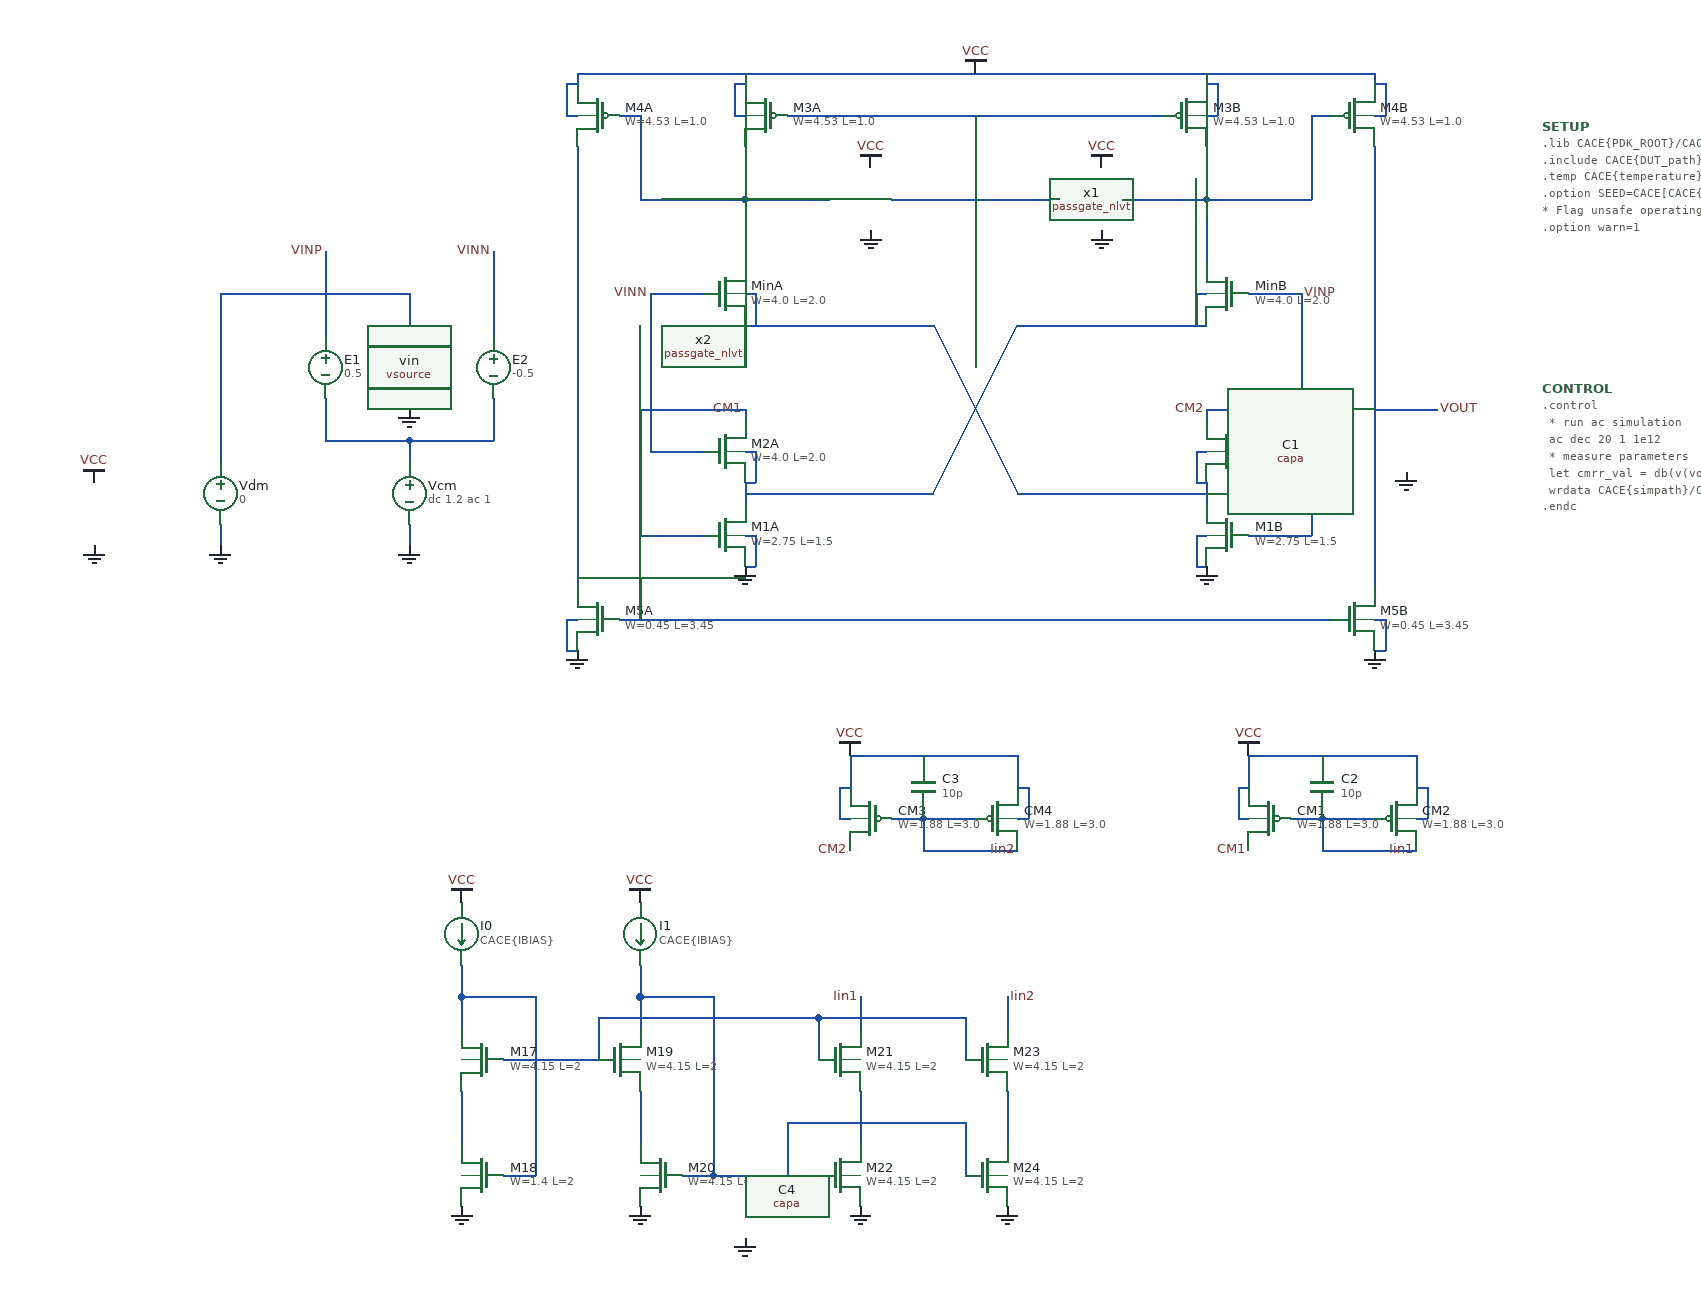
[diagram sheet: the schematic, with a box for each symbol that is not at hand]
v {xschem version=3.4.5 file_version=1.2
}
G {}
K {}
V {}
S {}
E {}
N 220 0 220 10 {
lab=CM2}
N -220 70 -220 90 {
lab=#net1}
N -320 0 -220 0 {
lab=CM1}
N -320 0 -320 120 {
lab=CM1}
N -320 120 -260 120 {
lab=CM1}
N 220 70 220 90 {
lab=#net2}
N -310 40 -260 40 {
lab=VINN}
N -310 -110 -260 -110 {
lab=VINN}
N 260 120 320 120 {
lab=CM2}
N 220 0 320 0 {
lab=CM2}
N 320 0 320 120 {
lab=CM2}
N 260 40 310 40 {
lab=VINP}
N 260 -110 310 -110 {
lab=VINP}
N -220 80 -40 80 {
lab=#net1}
N 40 -80 220 -80 {
lab=#net1}
N -220 -80 -40 -80 {
lab=#net2}
N 40 80 220 80 {
lab=#net2}
N 140 -200 220 -200 {
lab=#net3}
N -220 -200 -140 -200 {
lab=#net4}
N -80 -200 80 -200 {
lab=#net5}
N -180 -280 180 -280 {
lab=#net5}
N -380 -320 380 -320 {
lab=VCC}
N 320 -280 340 -280 {
lab=#net3}
N -340 -280 -320 -280 {
lab=#net4}
N -340 200 340 200 {
lab=#net6}
N -380 -250 -380 170 {
lab=#net6}
N -380 160 -320 160 {
lab=#net6}
N -320 160 -320 200 {
lab=#net6}
N 380 -250 380 170 {
lab=VOUT}
N -380 -320 -380 -310 {
lab=VCC}
N -220 -320 -220 -310 {
lab=VCC}
N 220 -320 220 -310 {
lab=VCC}
N 380 -320 380 -310 {
lab=VCC}
N 380 -0 440 0 {
lab=VOUT}
N -220 -110 -210 -110 {
lab=#net2}
N -210 -110 -210 -80 {
lab=#net2}
N 210 -110 220 -110 {
lab=#net1}
N 210 -110 210 -80 {
lab=#net1}
N -390 200 -380 200 {
lab=GND}
N -390 200 -390 230 {
lab=GND}
N -390 230 -380 230 {
lab=GND}
N -220 120 -210 120 {
lab=GND}
N -210 120 -210 150 {
lab=GND}
N -220 150 -210 150 {
lab=GND}
N -220 40 -210 40 {
lab=#net1}
N -210 40 -210 70 {
lab=#net1}
N -220 70 -210 70 {
lab=#net1}
N 210 120 220 120 {
lab=GND}
N 210 120 210 150 {
lab=GND}
N 210 150 220 150 {
lab=GND}
N 210 40 220 40 {
lab=#net2}
N 210 40 210 70 {
lab=#net2}
N 210 70 220 70 {
lab=#net2}
N 380 200 390 200 {
lab=GND}
N 390 200 390 230 {
lab=GND}
N 380 230 390 230 {
lab=GND}
N 220 -280 230 -280 {
lab=VCC}
N 230 -310 230 -280 {
lab=VCC}
N 220 -310 230 -310 {
lab=VCC}
N 380 -280 390 -280 {
lab=VCC}
N 390 -310 390 -280 {
lab=VCC}
N 380 -310 390 -310 {
lab=VCC}
N -230 -280 -220 -280 {
lab=VCC}
N -230 -310 -230 -280 {
lab=VCC}
N -230 -310 -220 -310 {
lab=VCC}
N -390 -280 -380 -280 {
lab=VCC}
N -390 -310 -390 -280 {
lab=VCC}
N -390 -310 -380 -310 {
lab=VCC}
N -220 0 -220 10 {
lab=CM1}
N -320 -280 -320 -200 {
lab=#net4}
N -320 -200 -220 -200 {
lab=#net4}
N 320 -280 320 -200 {
lab=#net3}
N 220 -200 320 -200 {
lab=#net3}
N -40 80 40 -80 {
lab=#net1}
N 220 -250 220 -200 {
lab=#net3}
N 220 -200 220 -140 {
lab=#net3}
N 310 -110 310 40 {
lab=VINP}
N -40 -80 40 80 {
lab=#net2}
N -310 -110 -310 40 {
lab=VINN}
N -220 -250 -220 -200 {
lab=#net4}
N -220 -200 -220 -140 {
lab=#net4}
N -0 -280 -0 -200 {
lab=#net5}
N -540 -60 -500 -60 {
lab=#net7}
N -720 -110 -720 50 {
lab=#net7}
N -720 -110 -540 -110 {
lab=#net7}
N -720 110 -720 130 {
lab=GND}
N -540 110 -540 130 {
lab=GND}
N -540 30 -460 30 {
lab=#net8}
N -540 30 -540 50 {
lab=#net8}
N -540 -20 -500 -20 {
lab=GND}
N -540 -20 -540 0 {
lab=GND}
N -620 -10 -620 30 {
lab=#net8}
N -460 -10 -460 30 {
lab=#net8}
N -540 -110 -540 -60 {
lab=#net7}
N -460 -150 -460 -70 {
lab=VINN}
N -620 -150 -620 -70 {
lab=VINP}
N -620 30 -540 30 {
lab=#net8}
N -580 -20 -540 -20 {
lab=GND}
N -580 -60 -540 -60 {
lab=#net7}
N 420 390 430 390 {
lab=VCC}
N 430 360 430 390 {
lab=VCC}
N 420 360 430 360 {
lab=VCC}
N 300 390 330 390 {
lab=Iin1}
N 330 390 380 390 {
lab=Iin1}
N 330 390 330 420 {
lab=Iin1}
N 330 420 420 420 {
lab=Iin1}
N 260 330 330 330 {
lab=VCC}
N 330 330 420 330 {
lab=VCC}
N 420 330 420 360 {
lab=VCC}
N 260 330 260 360 {
lab=VCC}
N 250 390 260 390 {
lab=VCC}
N 250 360 260 360 {
lab=VCC}
N 250 360 250 390 {
lab=VCC}
N 40 390 50 390 {
lab=VCC}
N 50 360 50 390 {
lab=VCC}
N 40 360 50 360 {
lab=VCC}
N -80 390 -50 390 {
lab=Iin2}
N -50 390 0 390 {
lab=Iin2}
N -50 390 -50 420 {
lab=Iin2}
N -50 420 40 420 {
lab=Iin2}
N -120 330 -50 330 {
lab=VCC}
N -50 330 40 330 {
lab=VCC}
N 40 330 40 360 {
lab=VCC}
N -120 330 -120 360 {
lab=VCC}
N -130 390 -120 390 {
lab=VCC}
N -130 360 -120 360 {
lab=VCC}
N -130 360 -130 390 {
lab=VCC}
N -490 560 -490 590 {
lab=#net7}
N -490 650 -490 700 {
lab=#net8}
N -450 730 -420 730 {
lab=#net7}
N -420 560 -420 730 {
lab=#net7}
N -490 560 -420 560 {
lab=#net7}
N -320 560 -320 590 {
lab=#net9}
N -320 650 -320 700 {
lab=#net10}
N -280 730 -250 730 {
lab=#net9}
N -250 560 -250 730 {
lab=#net9}
N -320 560 -250 560 {
lab=#net9}
N -110 560 -110 590 {
lab=Iin1}
N -110 650 -110 700 {
lab=#net11}
N -450 620 -420 620 {
lab=#net7}
N -250 730 -150 730 {
lab=#net9}
N -490 530 -490 560 {
lab=#net7}
N -320 530 -320 560 {
lab=#net9}
N -420 620 -360 620 {
lab=#net7}
N -360 580 -360 620 {
lab=#net7}
N -360 580 -150 580 {
lab=#net7}
N -150 580 -150 620 {
lab=#net7}
N 30 560 30 590 {
lab=Iin2}
N 30 650 30 700 {
lab=#net12}
N -10 580 -10 620 {
lab=#net7}
N -180 680 -180 730 {
lab=#net9}
N -180 680 -10 680 {
lab=#net9}
N -10 680 -10 730 {
lab=#net9}
N -150 580 -10 580 {
lab=#net7}
C {sky130_fd_pr/nfet_01v8.sym} 240 120 0 1 {name=M1B
W=2.75
L=1.5
nf=1
mult=1
ad="'int((nf+1)/2) * W/nf * 0.29'" 
pd="'2*int((nf+1)/2) * (W/nf + 0.29)'"
as="'int((nf+2)/2) * W/nf * 0.29'" 
ps="'2*int((nf+2)/2) * (W/nf + 0.29)'"
nrd="'0.29 / W'" nrs="'0.29 / W'"
sa=0 sb=0 sd=0
model=nfet_01v8
spiceprefix=X
}
C {sky130_fd_pr/nfet_01v8.sym} 240 40 0 1 {name=M2B
W=4.0
L=2.0
nf=1
mult=1
ad="'int((nf+1)/2) * W/nf * 0.29'" 
pd="'2*int((nf+1)/2) * (W/nf + 0.29)'"
as="'int((nf+2)/2) * W/nf * 0.29'" 
ps="'2*int((nf+2)/2) * (W/nf + 0.29)'"
nrd="'0.29 / W'" nrs="'0.29 / W'"
sa=0 sb=0 sd=0
model=nfet_01v8
spiceprefix=X
}
C {devices/gnd.sym} 220 150 0 0 {name=l1 lab=GND}
C {devices/lab_pin.sym} -310 -110 0 0 {name=p1 sig_type=std_logic lab=VINN}
C {sky130_fd_pr/nfet_01v8.sym} -240 120 0 0 {name=M1A
W=2.75
L=1.5
nf=1
mult=1
ad="'int((nf+1)/2) * W/nf * 0.29'" 
pd="'2*int((nf+1)/2) * (W/nf + 0.29)'"
as="'int((nf+2)/2) * W/nf * 0.29'" 
ps="'2*int((nf+2)/2) * (W/nf + 0.29)'"
nrd="'0.29 / W'" nrs="'0.29 / W'"
sa=0 sb=0 sd=0
model=nfet_01v8
spiceprefix=X
}
C {sky130_fd_pr/nfet_01v8.sym} -240 40 0 0 {name=M2A
W=4.0
L=2.0
nf=1
mult=1
ad="'int((nf+1)/2) * W/nf * 0.29'" 
pd="'2*int((nf+1)/2) * (W/nf + 0.29)'"
as="'int((nf+2)/2) * W/nf * 0.29'" 
ps="'2*int((nf+2)/2) * (W/nf + 0.29)'"
nrd="'0.29 / W'" nrs="'0.29 / W'"
sa=0 sb=0 sd=0
model=nfet_01v8
spiceprefix=X
}
C {devices/gnd.sym} -220 150 0 1 {name=l2 lab=GND}
C {devices/lab_pin.sym} 310 -110 0 1 {name=p6 sig_type=std_logic lab=VINP
}
C {sky130_fd_pr/pfet_01v8_lvt.sym} 200 -280 0 0 {name=M3B
W=4.53
L=1.0
nf=1
mult=2
ad="'int((nf+1)/2) * W/nf * 0.29'" 
pd="'2*int((nf+1)/2) * (W/nf + 0.29)'"
as="'int((nf+2)/2) * W/nf * 0.29'" 
ps="'2*int((nf+2)/2) * (W/nf + 0.29)'"
nrd="'0.29 / W'" nrs="'0.29 / W'"
sa=0 sb=0 sd=0
model=pfet_01v8_lvt
spiceprefix=X
}
C {sky130_fd_pr/pfet_01v8_lvt.sym} -200 -280 0 1 {name=M3A
W=4.53
L=1.0
nf=1
mult=2
ad="'int((nf+1)/2) * W/nf * 0.29'" 
pd="'2*int((nf+1)/2) * (W/nf + 0.29)'"
as="'int((nf+2)/2) * W/nf * 0.29'" 
ps="'2*int((nf+2)/2) * (W/nf + 0.29)'"
nrd="'0.29 / W'" nrs="'0.29 / W'"
sa=0 sb=0 sd=0
model=pfet_01v8_lvt
spiceprefix=X
}
C {devices/vdd.sym} 0 -320 0 0 {name=l6 lab=VCC}
C {sky130_fd_pr/pfet_01v8_lvt.sym} 360 -280 0 0 {name=M4B
W=4.53
L=1.0
nf=1
mult=2
ad="'int((nf+1)/2) * W/nf * 0.29'" 
pd="'2*int((nf+1)/2) * (W/nf + 0.29)'"
as="'int((nf+2)/2) * W/nf * 0.29'" 
ps="'2*int((nf+2)/2) * (W/nf + 0.29)'"
nrd="'0.29 / W'" nrs="'0.29 / W'"
sa=0 sb=0 sd=0
model=pfet_01v8_lvt
spiceprefix=X
}
C {sky130_fd_pr/pfet_01v8_lvt.sym} -360 -280 0 1 {name=M4A
W=4.53
L=1.0
nf=1
mult=2
ad="'int((nf+1)/2) * W/nf * 0.29'" 
pd="'2*int((nf+1)/2) * (W/nf + 0.29)'"
as="'int((nf+2)/2) * W/nf * 0.29'" 
ps="'2*int((nf+2)/2) * (W/nf + 0.29)'"
nrd="'0.29 / W'" nrs="'0.29 / W'"
sa=0 sb=0 sd=0
model=pfet_01v8_lvt
spiceprefix=X
}
C {devices/gnd.sym} -380 230 0 1 {name=l8 lab=GND}
C {devices/gnd.sym} 380 230 0 1 {name=l9 lab=GND}
C {devices/lab_pin.sym} 440 0 2 0 {name=p2 sig_type=std_logic lab=VOUT}
C {devices/lab_pin.sym} -620 -150 2 1 {name=p4 sig_type=std_logic lab=VINP
}
C {devices/lab_pin.sym} -460 -150 0 0 {name=p5 sig_type=std_logic lab=VINN}
C {devices/capa.sym} 410 30 0 0 {name=C1
m=1
value=CACE\{cl\}
footprint=1206
device="ceramic capacitor"}
C {devices/gnd.sym} 410 60 0 0 {name=l12 lab=GND}
C {sky130_fd_pr/nfet_01v8.sym} -360 200 0 1 {name=M5A
W=0.45
L=3.45
nf=1
mult=2
ad="'int((nf+1)/2) * W/nf * 0.29'" 
pd="'2*int((nf+1)/2) * (W/nf + 0.29)'"
as="'int((nf+2)/2) * W/nf * 0.29'" 
ps="'2*int((nf+2)/2) * (W/nf + 0.29)'"
nrd="'0.29 / W'" nrs="'0.29 / W'"
sa=0 sb=0 sd=0
model=nfet_01v8
spiceprefix=X
}
C {sky130_fd_pr/nfet_01v8.sym} 360 200 0 0 {name=M5B
W=0.45
L=3.45
nf=1
mult=2
ad="'int((nf+1)/2) * W/nf * 0.29'" 
pd="'2*int((nf+1)/2) * (W/nf + 0.29)'"
as="'int((nf+2)/2) * W/nf * 0.29'" 
ps="'2*int((nf+2)/2) * (W/nf + 0.29)'"
nrd="'0.29 / W'" nrs="'0.29 / W'"
sa=0 sb=0 sd=0
model=nfet_01v8
spiceprefix=X
}
C {sky130_fd_pr/nfet_01v8.sym} -240 -110 0 0 {name=MinA
W=4.0
L=2.0
nf=1
mult=1
ad="'int((nf+1)/2) * W/nf * 0.29'" 
pd="'2*int((nf+1)/2) * (W/nf + 0.29)'"
as="'int((nf+2)/2) * W/nf * 0.29'" 
ps="'2*int((nf+2)/2) * (W/nf + 0.29)'"
nrd="'0.29 / W'" nrs="'0.29 / W'"
sa=0 sb=0 sd=0
model=nfet_01v8
spiceprefix=X
}
C {sky130_fd_pr/nfet_01v8.sym} 240 -110 0 1 {name=MinB
W=4.0
L=2.0
nf=1
mult=1
ad="'int((nf+1)/2) * W/nf * 0.29'" 
pd="'2*int((nf+1)/2) * (W/nf + 0.29)'"
as="'int((nf+2)/2) * W/nf * 0.29'" 
ps="'2*int((nf+2)/2) * (W/nf + 0.29)'"
nrd="'0.29 / W'" nrs="'0.29 / W'"
sa=0 sb=0 sd=0
model=nfet_01v8
spiceprefix=X
}
C {devices/code_shown.sym} 540 -270 0 0 {name=SETUP
simulator=ngspice
only_toplevel=false
value="
.lib CACE\{PDK_ROOT\}/CACE\{PDK\}/libs.tech/combined/sky130.lib.spice CACE\{corner\}

.include CACE\{DUT_path\}

.temp CACE\{temperature\}

.option SEED=CACE[CACE\{seed=12345\} + CACE\{iterations=0\}]

* Flag unsafe operating conditions (exceeds models' specified limits)
.option warn=1
"}
C {devices/code_shown.sym} 540 -20 0 0 {name=CONTROL
simulator=ngspice
only_toplevel=false
value="
.control
    * run ac simulation
    ac dec 20 1 1e12

    * measure parameters
    let cmrr_val = db(v(vout)) 180/pi*ph(v(vout))

    wrdata CACE\{simpath\}/CACE\{filename\}_CACE\{N\}.data cmrr_val

.endc
"}
C {sky130_tests/passgate_nlvt.sym} -100 -200 2 0 {name=x2 W_N=0.5 L_N=4 W_P=3 L_P=4 VCCBPIN=VCC VSSBPIN=VSS m=1}
C {sky130_tests/passgate_nlvt.sym} 120 -200 2 1 {name=x1 W_N=0.5 L_N=4 W_P=3 L_P=4 VCCBPIN=VCC VSSBPIN=VSS m=1}
C {devices/vdd.sym} -100 -230 0 0 {name=l20 lab=VCC}
C {devices/vdd.sym} 120 -230 0 0 {name=l21 lab=VCC}
C {devices/gnd.sym} -100 -170 0 1 {name=l22 lab=GND}
C {devices/gnd.sym} 120 -170 0 0 {name=l23 lab=GND}
C {devices/lab_pin.sym} -220 0 1 0 {name=p8 sig_type=std_logic lab=CM1}
C {devices/lab_pin.sym} 220 0 1 0 {name=p7 sig_type=std_logic lab=CM2}
C {devices/vcvs.sym} -620 -40 0 1 {name=E1 value=0.5}
C {devices/vcvs.sym} -460 -40 0 0 {name=E2 value=-0.5}
C {devices/vsource.sym} -720 80 0 1 {name=Vdm value=0 savecurrent=false}
C {devices/vsource.sym} -540 80 0 0 {name=Vcm value="dc 1.2 ac 1" savecurrent=false}
C {devices/gnd.sym} -720 130 0 0 {name=l10 lab=GND}
C {devices/gnd.sym} -540 130 0 0 {name=l11 lab=GND}
C {devices/gnd.sym} -540 0 0 0 {name=l13 lab=GND}
C {devices/vsource.sym} -840 100 0 0 {name=vin value=CACE\{vcc\} savecurrent=false}
C {devices/gnd.sym} -840 130 0 0 {name=l14 lab=GND}
C {devices/vdd.sym} -840 70 0 0 {name=l15 lab=VCC}
C {devices/vdd.sym} 260 330 0 0 {name=l3 lab=VCC}
C {sky130_fd_pr/pfet_01v8_lvt.sym} 280 390 0 1 {name=CM1
W=1.88
L=3.0
nf=1
mult=2
ad="'int((nf+1)/2) * W/nf * 0.29'" 
pd="'2*int((nf+1)/2) * (W/nf + 0.29)'"
as="'int((nf+2)/2) * W/nf * 0.29'" 
ps="'2*int((nf+2)/2) * (W/nf + 0.29)'"
nrd="'0.29 / W'" nrs="'0.29 / W'"
sa=0 sb=0 sd=0
model=pfet_01v8_lvt
spiceprefix=X
}
C {sky130_fd_pr/pfet_01v8_lvt.sym} 400 390 0 0 {name=CM2
W=1.88
L=3.0
nf=1
mult=2
ad="'int((nf+1)/2) * W/nf * 0.29'" 
pd="'2*int((nf+1)/2) * (W/nf + 0.29)'"
as="'int((nf+2)/2) * W/nf * 0.29'" 
ps="'2*int((nf+2)/2) * (W/nf + 0.29)'"
nrd="'0.29 / W'" nrs="'0.29 / W'"
sa=0 sb=0 sd=0
model=pfet_01v8_lvt
spiceprefix=X
}
C {devices/lab_pin.sym} 260 420 3 0 {name=p9 sig_type=std_logic lab=CM1}
C {devices/capa.sym} 330 360 0 0 {name=C2
m=1
value=10p
footprint=1206
device="ceramic capacitor"}
C {devices/vdd.sym} -120 330 0 0 {name=l7 lab=VCC}
C {sky130_fd_pr/pfet_01v8_lvt.sym} -100 390 0 1 {name=CM3
W=1.88
L=3.0
nf=1
mult=2
ad="'int((nf+1)/2) * W/nf * 0.29'" 
pd="'2*int((nf+1)/2) * (W/nf + 0.29)'"
as="'int((nf+2)/2) * W/nf * 0.29'" 
ps="'2*int((nf+2)/2) * (W/nf + 0.29)'"
nrd="'0.29 / W'" nrs="'0.29 / W'"
sa=0 sb=0 sd=0
model=pfet_01v8_lvt
spiceprefix=X
}
C {sky130_fd_pr/pfet_01v8_lvt.sym} 20 390 0 0 {name=CM4
W=1.88
L=3.0
nf=1
mult=2
ad="'int((nf+1)/2) * W/nf * 0.29'" 
pd="'2*int((nf+1)/2) * (W/nf + 0.29)'"
as="'int((nf+2)/2) * W/nf * 0.29'" 
ps="'2*int((nf+2)/2) * (W/nf + 0.29)'"
nrd="'0.29 / W'" nrs="'0.29 / W'"
sa=0 sb=0 sd=0
model=pfet_01v8_lvt
spiceprefix=X
}
C {devices/lab_pin.sym} -120 420 3 0 {name=p11 sig_type=std_logic lab=CM2}
C {devices/capa.sym} -50 360 0 0 {name=C3
m=1
value=10p
footprint=1206
device="ceramic capacitor"}
C {devices/isource.sym} -490 500 0 0 {name=I0 value=CACE\{IBIAS\}}
C {devices/isource.sym} -320 500 0 0 {name=I1 value=CACE\{IBIAS\}}
C {sky130_fd_pr/nfet3_01v8.sym} -470 620 0 1 {name=M17
L=2
W=4.15
body=GND
nf=2
mult=1
ad="'int((nf+1)/2) * W/nf * 0.29'" 
pd="'2*int((nf+1)/2) * (W/nf + 0.29)'"
as="'int((nf+2)/2) * W/nf * 0.29'" 
ps="'2*int((nf+2)/2) * (W/nf + 0.29)'"
nrd="'0.29 / W'" nrs="'0.29 / W'"
sa=0 sb=0 sd=0
model=nfet_01v8
spiceprefix=X
}
C {sky130_fd_pr/nfet3_01v8.sym} -470 730 0 1 {name=M18
L=2
W=1.4
body=GND
nf=1
mult=1
ad="'int((nf+1)/2) * W/nf * 0.29'" 
pd="'2*int((nf+1)/2) * (W/nf + 0.29)'"
as="'int((nf+2)/2) * W/nf * 0.29'" 
ps="'2*int((nf+2)/2) * (W/nf + 0.29)'"
nrd="'0.29 / W'" nrs="'0.29 / W'"
sa=0 sb=0 sd=0
model=nfet_01v8
spiceprefix=X
}
C {sky130_fd_pr/nfet3_01v8.sym} -340 620 0 0 {name=M19
L=2
W=4.15
body=GND
nf=2
mult=1
ad="'int((nf+1)/2) * W/nf * 0.29'" 
pd="'2*int((nf+1)/2) * (W/nf + 0.29)'"
as="'int((nf+2)/2) * W/nf * 0.29'" 
ps="'2*int((nf+2)/2) * (W/nf + 0.29)'"
nrd="'0.29 / W'" nrs="'0.29 / W'"
sa=0 sb=0 sd=0
model=nfet_01v8
spiceprefix=X
}
C {sky130_fd_pr/nfet3_01v8.sym} -300 730 0 1 {name=M20
L=2
W=4.15
body=GND
nf=2
mult=1
ad="'int((nf+1)/2) * W/nf * 0.29'" 
pd="'2*int((nf+1)/2) * (W/nf + 0.29)'"
as="'int((nf+2)/2) * W/nf * 0.29'" 
ps="'2*int((nf+2)/2) * (W/nf + 0.29)'"
nrd="'0.29 / W'" nrs="'0.29 / W'"
sa=0 sb=0 sd=0
model=nfet_01v8
spiceprefix=X
}
C {sky130_fd_pr/nfet3_01v8.sym} -130 620 0 0 {name=M21
L=2
W=4.15
body=GND
nf=2
mult=1
ad="'int((nf+1)/2) * W/nf * 0.29'" 
pd="'2*int((nf+1)/2) * (W/nf + 0.29)'"
as="'int((nf+2)/2) * W/nf * 0.29'" 
ps="'2*int((nf+2)/2) * (W/nf + 0.29)'"
nrd="'0.29 / W'" nrs="'0.29 / W'"
sa=0 sb=0 sd=0
model=nfet_01v8
spiceprefix=X
}
C {sky130_fd_pr/nfet3_01v8.sym} -130 730 0 0 {name=M22
L=2
W=4.15
body=GND
nf=2
mult=1
ad="'int((nf+1)/2) * W/nf * 0.29'" 
pd="'2*int((nf+1)/2) * (W/nf + 0.29)'"
as="'int((nf+2)/2) * W/nf * 0.29'" 
ps="'2*int((nf+2)/2) * (W/nf + 0.29)'"
nrd="'0.29 / W'" nrs="'0.29 / W'"
sa=0 sb=0 sd=0
model=nfet_01v8
spiceprefix=X
}
C {devices/gnd.sym} -110 760 0 0 {name=l16 lab=GND}
C {devices/gnd.sym} -320 760 0 0 {name=l17 lab=GND}
C {devices/gnd.sym} -490 760 0 0 {name=l18 lab=GND}
C {devices/lab_pin.sym} -110 560 0 0 {name=p41 sig_type=std_logic lab=Iin1}
C {devices/lab_pin.sym} 30 560 0 1 {name=p42 sig_type=std_logic lab=Iin2}
C {sky130_fd_pr/nfet3_01v8.sym} 10 620 0 0 {name=M23
L=2
W=4.15
body=GND
nf=2
mult=1
ad="'int((nf+1)/2) * W/nf * 0.29'" 
pd="'2*int((nf+1)/2) * (W/nf + 0.29)'"
as="'int((nf+2)/2) * W/nf * 0.29'" 
ps="'2*int((nf+2)/2) * (W/nf + 0.29)'"
nrd="'0.29 / W'" nrs="'0.29 / W'"
sa=0 sb=0 sd=0
model=nfet_01v8
spiceprefix=X
}
C {sky130_fd_pr/nfet3_01v8.sym} 10 730 0 0 {name=M24
L=2
W=4.15
body=GND
nf=2
mult=1
ad="'int((nf+1)/2) * W/nf * 0.29'" 
pd="'2*int((nf+1)/2) * (W/nf + 0.29)'"
as="'int((nf+2)/2) * W/nf * 0.29'" 
ps="'2*int((nf+2)/2) * (W/nf + 0.29)'"
nrd="'0.29 / W'" nrs="'0.29 / W'"
sa=0 sb=0 sd=0
model=nfet_01v8
spiceprefix=X
}
C {devices/gnd.sym} 30 760 0 0 {name=l19 lab=GND}
C {devices/capa.sym} -220 760 0 0 {name=C4
m=1
value=10p
footprint=1206
device="ceramic capacitor"}
C {devices/gnd.sym} -220 790 0 0 {name=l24 lab=GND}
C {devices/lab_pin.sym} 420 420 3 0 {name=p3 sig_type=std_logic lab=Iin1}
C {devices/lab_pin.sym} 40 420 1 1 {name=p10 sig_type=std_logic lab=Iin2}
C {devices/vdd.sym} -490 470 0 0 {name=l4 lab=VCC}
C {devices/vdd.sym} -320 470 0 0 {name=l5 lab=VCC}
